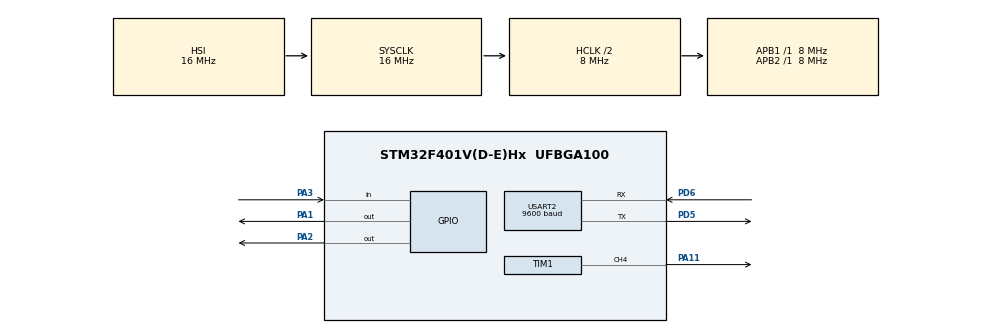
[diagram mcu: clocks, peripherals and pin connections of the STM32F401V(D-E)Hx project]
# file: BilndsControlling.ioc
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Mcu.Family=STM32F4
Mcu.Name=STM32F401V(D-E)Hx
Mcu.Package=UFBGA100
NVIC.PriorityGroup=NVIC_PRIORITYGROUP_4
PA1.Signal=GPIO_Output
PA11.Signal=S_TIM1_CH4
PA2.Signal=GPIO_Output
PA3.Signal=GPIO_Input
PD5.Mode=Asynchronous
PD5.Signal=USART2_TX
PD6.Mode=Asynchronous
PD6.Signal=USART2_RX
ProjectManager.HeapSize=0x200
ProjectManager.StackSize=0x400
ProjectManager.TargetToolchain=STM32CubeIDE
RCC.AHBCLKDivider=RCC_SYSCLK_DIV2
RCC.AHBFreq_Value=8000000
RCC.APB1Freq_Value=8000000
RCC.APB1TimFreq_Value=8000000
RCC.APB2Freq_Value=8000000
RCC.APB2TimFreq_Value=8000000
RCC.CortexFreq_Value=8000000
RCC.HCLKFreq_Value=8000000
RCC.HSE_VALUE=25000000
RCC.HSI_VALUE=16000000
RCC.LSE_VALUE=32768
RCC.SYSCLKFreq_VALUE=16000000
RCC.VCOOutputFreq_Value=192000000
SH.S_TIM1_CH4.0=TIM1_CH4,PWM Generation4 CH4
TIM1.Channel-PWM\ Generation4\ CH4=TIM_CHANNEL_4
TIM1.Period=1000
TIM1.Prescaler=80
TIM1.Pulse-PWM\ Generation4\ CH4=500
USART2.BaudRate=9600
USART2.VirtualMode=VM_ASYNC
VP_TIM1_VS_ClockSourceINT.Mode=Internal
board=custom

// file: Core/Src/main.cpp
/* USER CODE BEGIN Header */
/**
  ******************************************************************************
  * @file           : main.c
  * @brief          : Main program body
  ******************************************************************************
  * @attention
  *
  * Copyright (c) 2024 STMicroelectronics.
  * All rights reserved.
  *
  * This software is licensed under terms that can be found in the LICENSE file
  * in the root directory of this software component.
  * If no LICENSE file comes with this software, it is provided AS-IS.
  *
  ******************************************************************************
  */
/* USER CODE END Header */
#include "main.h"
#include "string.h"
/* USER CODE BEGIN Includes */
#include "MotorController.h"
/* USER CODE END Includes */

TIM_HandleTypeDef htim1;

UART_HandleTypeDef huart2;

/* USER CODE BEGIN PV */
MotorController motorController;
/* USER CODE END PV */

void SystemClock_Config(void);
static void MX_GPIO_Init(void);
static void MX_TIM1_Init(void);
static void MX_USART2_UART_Init(void);

int main(void)
{

  /* MCU Configuration--------------------------------------------------------*/

  /* Reset of all peripherals, Initializes the Flash interface and the Systick. */
  HAL_Init();

  /* Configure the system clock */
  SystemClock_Config();

  /* Initialize all configured peripherals */
  MX_GPIO_Init();
  MX_TIM1_Init();
  MX_USART2_UART_Init();
  /* USER CODE BEGIN 2 */
  HAL_TIM_PWM_Start(&htim1,TIM_CHANNEL_4);
  /* USER CODE END 2 */

  /* Infinite loop */
  while (1)
  {
	  if(HAL_GPIO_ReadPin(GPIOA, GPIO_PIN_7) == GPIO_PIN_RESET){
		  motorController.handleEvent();
	  }
	  HAL_Delay(100);
  }
}

void SystemClock_Config(void)
{
  RCC_OscInitTypeDef RCC_OscInitStruct = {0};
  RCC_ClkInitTypeDef RCC_ClkInitStruct = {0};

  /** Configure the main internal regulator output voltage
  */
  __HAL_RCC_PWR_CLK_ENABLE();
  __HAL_PWR_VOLTAGESCALING_CONFIG(PWR_REGULATOR_VOLTAGE_SCALE2);

  /** Initializes the RCC Oscillators according to the specified parameters
  * in the RCC_OscInitTypeDef structure.
  */
  RCC_OscInitStruct.OscillatorType = RCC_OSCILLATORTYPE_HSI;
  RCC_OscInitStruct.HSIState = RCC_HSI_ON;
  RCC_OscInitStruct.HSICalibrationValue = RCC_HSICALIBRATION_DEFAULT;
  RCC_OscInitStruct.PLL.PLLState = RCC_PLL_NONE;
  if (HAL_RCC_OscConfig(&RCC_OscInitStruct) != HAL_OK)
  {
    Error_Handler();
  }

  /** Initializes the CPU, AHB and APB buses clocks
  */
  RCC_ClkInitStruct.ClockType = RCC_CLOCKTYPE_HCLK|RCC_CLOCKTYPE_SYSCLK
                              |RCC_CLOCKTYPE_PCLK1|RCC_CLOCKTYPE_PCLK2;
  RCC_ClkInitStruct.SYSCLKSource = RCC_SYSCLKSOURCE_HSI;
  RCC_ClkInitStruct.AHBCLKDivider = RCC_SYSCLK_DIV2;
  RCC_ClkInitStruct.APB1CLKDivider = RCC_HCLK_DIV1;
  RCC_ClkInitStruct.APB2CLKDivider = RCC_HCLK_DIV1;

  if (HAL_RCC_ClockConfig(&RCC_ClkInitStruct, FLASH_LATENCY_0) != HAL_OK)
  {
    Error_Handler();
  }
}

static void MX_TIM1_Init(void)
{

  TIM_ClockConfigTypeDef sClockSourceConfig = {0};
  TIM_MasterConfigTypeDef sMasterConfig = {0};
  TIM_OC_InitTypeDef sConfigOC = {0};
  TIM_BreakDeadTimeConfigTypeDef sBreakDeadTimeConfig = {0};

  htim1.Instance = TIM1;
  htim1.Init.Prescaler = 80;
  htim1.Init.CounterMode = TIM_COUNTERMODE_UP;
  htim1.Init.Period = 1000;
  htim1.Init.ClockDivision = TIM_CLOCKDIVISION_DIV1;
  htim1.Init.RepetitionCounter = 0;
  htim1.Init.AutoReloadPreload = TIM_AUTORELOAD_PRELOAD_DISABLE;
  if (HAL_TIM_Base_Init(&htim1) != HAL_OK)
  {
    Error_Handler();
  }
  sClockSourceConfig.ClockSource = TIM_CLOCKSOURCE_INTERNAL;
  if (HAL_TIM_ConfigClockSource(&htim1, &sClockSourceConfig) != HAL_OK)
  {
    Error_Handler();
  }
  if (HAL_TIM_PWM_Init(&htim1) != HAL_OK)
  {
    Error_Handler();
  }
  sMasterConfig.MasterOutputTrigger = TIM_TRGO_RESET;
  sMasterConfig.MasterSlaveMode = TIM_MASTERSLAVEMODE_DISABLE;
  if (HAL_TIMEx_MasterConfigSynchronization(&htim1, &sMasterConfig) != HAL_OK)
  {
    Error_Handler();
  }
  sConfigOC.OCMode = TIM_OCMODE_PWM1;
  sConfigOC.Pulse = 500;
  sConfigOC.OCPolarity = TIM_OCPOLARITY_HIGH;
  sConfigOC.OCFastMode = TIM_OCFAST_DISABLE;
  sConfigOC.OCIdleState = TIM_OCIDLESTATE_RESET;
  sConfigOC.OCNIdleState = TIM_OCNIDLESTATE_RESET;
  if (HAL_TIM_PWM_ConfigChannel(&htim1, &sConfigOC, TIM_CHANNEL_4) != HAL_OK)
  {
    Error_Handler();
  }
  sBreakDeadTimeConfig.OffStateRunMode = TIM_OSSR_DISABLE;
  sBreakDeadTimeConfig.OffStateIDLEMode = TIM_OSSI_DISABLE;
  sBreakDeadTimeConfig.LockLevel = TIM_LOCKLEVEL_OFF;
  sBreakDeadTimeConfig.DeadTime = 0;
  sBreakDeadTimeConfig.BreakState = TIM_BREAK_DISABLE;
  sBreakDeadTimeConfig.BreakPolarity = TIM_BREAKPOLARITY_HIGH;
  sBreakDeadTimeConfig.AutomaticOutput = TIM_AUTOMATICOUTPUT_DISABLE;
  if (HAL_TIMEx_ConfigBreakDeadTime(&htim1, &sBreakDeadTimeConfig) != HAL_OK)
  {
    Error_Handler();
  }
  HAL_TIM_MspPostInit(&htim1);

}

static void MX_USART2_UART_Init(void)
{

  huart2.Instance = USART2;
  huart2.Init.BaudRate = 9600;
  huart2.Init.WordLength = UART_WORDLENGTH_8B;
  huart2.Init.StopBits = UART_STOPBITS_1;
  huart2.Init.Parity = UART_PARITY_NONE;
  huart2.Init.Mode = UART_MODE_TX_RX;
  huart2.Init.HwFlowCtl = UART_HWCONTROL_NONE;
  huart2.Init.OverSampling = UART_OVERSAMPLING_16;
  if (HAL_UART_Init(&huart2) != HAL_OK)
  {
    Error_Handler();
  }

}

static void MX_GPIO_Init(void)
{
  GPIO_InitTypeDef GPIO_InitStruct = {0};

  /* GPIO Ports Clock Enable */
  __HAL_RCC_GPIOD_CLK_ENABLE();
  __HAL_RCC_GPIOA_CLK_ENABLE();

  /*Configure GPIO pin Output Level */
  HAL_GPIO_WritePin(GPIOA, GPIO_PIN_2|GPIO_PIN_1, GPIO_PIN_RESET);

  /*Configure GPIO pins : PA2 PA1 */
  GPIO_InitStruct.Pin = GPIO_PIN_2|GPIO_PIN_1|GPIO_PIN_3|GPIO_PIN_4;
  GPIO_InitStruct.Mode = GPIO_MODE_OUTPUT_PP;
  GPIO_InitStruct.Pull = GPIO_NOPULL;
  GPIO_InitStruct.Speed = GPIO_SPEED_FREQ_LOW;
  HAL_GPIO_Init(GPIOA, &GPIO_InitStruct);

  /*Configure GPIO pin : PA3 */
  GPIO_InitStruct.Pin = GPIO_PIN_5;
  GPIO_InitStruct.Mode = GPIO_MODE_INPUT;
  GPIO_InitStruct.Pull = GPIO_PULLUP;
  HAL_GPIO_Init(GPIOA, &GPIO_InitStruct);

}

void Error_Handler(void)
{
  __disable_irq();
  while (1)
  {
  }
}
